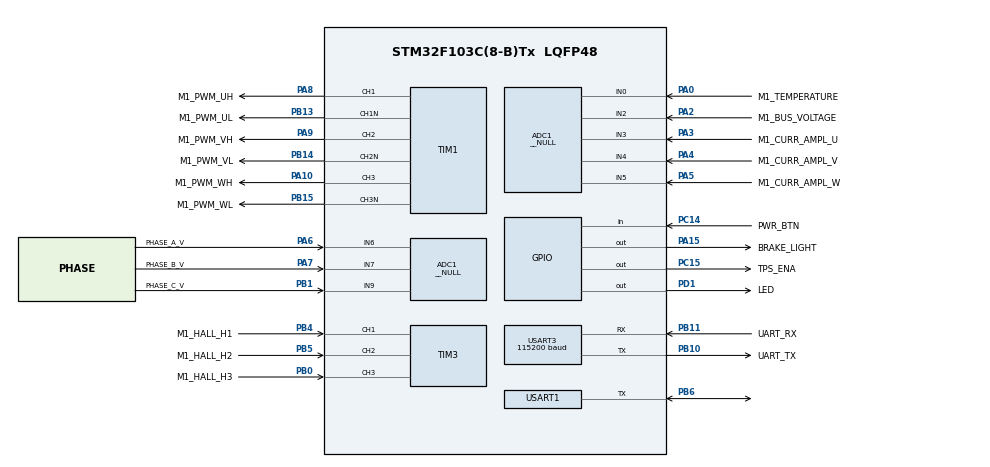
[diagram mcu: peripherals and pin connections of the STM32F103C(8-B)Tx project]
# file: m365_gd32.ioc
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ADC1.Channel-1\#ChannelInjectedConversion=ADC_CHANNEL_3
ADC1.Channel-1\#ChannelRegularConversion=ADC_CHANNEL_2
ADC1.Channel-2\#ChannelInjectedConversion=ADC_CHANNEL_4
ADC1.Channel-2\#ChannelRegularConversion=ADC_CHANNEL_0
ADC1.Channel-3\#ChannelInjectedConversion=ADC_CHANNEL_5
ADC1.Channel-4\#ChannelRegularConversion=ADC_CHANNEL_6
ADC1.Channel-5\#ChannelRegularConversion=ADC_CHANNEL_7
ADC1.Channel-6\#ChannelRegularConversion=ADC_CHANNEL_9
ADC1.ContinuousConvMode=DISABLE
ADC1.DataAlign=ADC_DATAALIGN_LEFT
ADC1.DiscontinuousConvMode=DISABLE
ADC1.EnableAnalogWatchDog=false
ADC1.EnableInjectedConversion=ENABLE
ADC1.EnableRegularConversion=ENABLE
ADC1.ExternalTrigConv=ADC_SOFTWARE_START
ADC1.ExternalTrigInjecConv=ADC_EXTERNALTRIGINJECCONV_T1_CC4
ADC1.InjNumberOfConversion=3
ADC1.InjectedConvMode=Discontinuous
ADC1.InjectedOffset-1\#ChannelInjectedConversion=0
ADC1.InjectedOffset-2\#ChannelInjectedConversion=0
ADC1.InjectedOffset-3\#ChannelInjectedConversion=0
ADC1.Mode=__NULL
ADC1.NbrOfConversion=5
ADC1.NbrOfConversionFlag=1
ADC1.Rank-1\#ChannelRegularConversion=1
ADC1.Rank-2\#ChannelRegularConversion=2
ADC1.Rank-4\#ChannelRegularConversion=3
ADC1.Rank-5\#ChannelRegularConversion=4
ADC1.Rank-6\#ChannelRegularConversion=5
ADC1.SamplingTime-1\#ChannelInjectedConversion=ADC_SAMPLETIME_1CYCLE_5
ADC1.SamplingTime-1\#ChannelRegularConversion=ADC_SAMPLETIME_1CYCLE_5
ADC1.SamplingTime-2\#ChannelInjectedConversion=ADC_SAMPLETIME_1CYCLE_5
ADC1.SamplingTime-2\#ChannelRegularConversion=ADC_SAMPLETIME_1CYCLE_5
ADC1.SamplingTime-3\#ChannelInjectedConversion=ADC_SAMPLETIME_1CYCLE_5
ADC1.SamplingTime-4\#ChannelRegularConversion=ADC_SAMPLETIME_1CYCLE_5
ADC1.SamplingTime-5\#ChannelRegularConversion=ADC_SAMPLETIME_1CYCLE_5
ADC1.SamplingTime-6\#ChannelRegularConversion=ADC_SAMPLETIME_1CYCLE_5
ADC1.ScanConvMode=ADC_SCAN_ENABLE
ADC1.master=1
ADC2.Channel-1\#ChannelInjectedConversion=ADC_CHANNEL_3
ADC2.Channel-2\#ChannelInjectedConversion=ADC_CHANNEL_4
ADC2.Channel-3\#ChannelInjectedConversion=ADC_CHANNEL_5
ADC2.ContinuousConvMode=DISABLE
ADC2.DataAlign=ADC_DATAALIGN_LEFT
ADC2.DiscontinuousConvMode=DISABLE
ADC2.EnableAnalogWatchDog=false
ADC2.EnableInjectedConversion=ENABLE
ADC2.EnableRegularConversion=DISABLE
ADC2.ExternalTrigInjecConv=ADC_EXTERNALTRIGINJECCONV_T1_CC4
ADC2.ExternalTrigInjecConvEdge=ADC_EXTERNALTRIGINJECCONVEDGE_RISING
ADC2.InjNumberOfConversion=3
ADC2.InjectedConvMode=Discontinuous
ADC2.InjectedOffset-1\#ChannelInjectedConversion=0
ADC2.InjectedOffset-2\#ChannelInjectedConversion=0
ADC2.InjectedOffset-3\#ChannelInjectedConversion=0
ADC2.Mode=__NULL
ADC2.Rank-1\#ChannelInjectedConversion=1
ADC2.Rank-2\#ChannelInjectedConversion=2
ADC2.Rank-3\#ChannelInjectedConversion=3
ADC2.SamplingTime-1\#ChannelInjectedConversion=ADC_SAMPLETIME_1CYCLE_5
ADC2.SamplingTime-2\#ChannelInjectedConversion=ADC_SAMPLETIME_1CYCLE_5
ADC2.SamplingTime-3\#ChannelInjectedConversion=ADC_SAMPLETIME_1CYCLE_5
ADC2.ScanConvMode=ADC_SCAN_ENABLE
Dma.ADC1.0.Direction=DMA_PERIPH_TO_MEMORY
Dma.ADC1.0.Instance=DMA1_Channel1
Dma.ADC1.0.MemDataAlignment=DMA_MDATAALIGN_HALFWORD
Dma.ADC1.0.MemInc=DMA_MINC_DISABLE
Dma.ADC1.0.Mode=DMA_CIRCULAR
Dma.ADC1.0.PeriphDataAlignment=DMA_PDATAALIGN_HALFWORD
Dma.ADC1.0.PeriphInc=DMA_PINC_DISABLE
Dma.ADC1.0.Priority=DMA_PRIORITY_LOW
Dma.Request0=ADC1
Dma.Request1=USART1_TX
Dma.Request2=USART1_RX
Dma.Request3=USART3_RX
Dma.Request4=USART3_TX
Dma.USART1_RX.2.Direction=DMA_PERIPH_TO_MEMORY
Dma.USART1_RX.2.Instance=DMA1_Channel5
Dma.USART1_RX.2.MemDataAlignment=DMA_MDATAALIGN_BYTE
Dma.USART1_RX.2.MemInc=DMA_MINC_ENABLE
Dma.USART1_RX.2.Mode=DMA_CIRCULAR
Dma.USART1_RX.2.PeriphDataAlignment=DMA_PDATAALIGN_BYTE
Dma.USART1_RX.2.PeriphInc=DMA_PINC_DISABLE
Dma.USART1_RX.2.Priority=DMA_PRIORITY_LOW
Dma.USART1_TX.1.Direction=DMA_MEMORY_TO_PERIPH
Dma.USART1_TX.1.Instance=DMA1_Channel4
Dma.USART1_TX.1.MemDataAlignment=DMA_MDATAALIGN_BYTE
Dma.USART1_TX.1.MemInc=DMA_MINC_ENABLE
Dma.USART1_TX.1.Mode=DMA_NORMAL
Dma.USART1_TX.1.PeriphDataAlignment=DMA_PDATAALIGN_BYTE
Dma.USART1_TX.1.PeriphInc=DMA_PINC_DISABLE
Dma.USART1_TX.1.Priority=DMA_PRIORITY_LOW
Dma.USART3_RX.3.Direction=DMA_PERIPH_TO_MEMORY
Dma.USART3_RX.3.Instance=DMA1_Channel3
Dma.USART3_RX.3.MemDataAlignment=DMA_MDATAALIGN_BYTE
Dma.USART3_RX.3.MemInc=DMA_MINC_ENABLE
Dma.USART3_RX.3.Mode=DMA_CIRCULAR
Dma.USART3_RX.3.PeriphDataAlignment=DMA_PDATAALIGN_BYTE
Dma.USART3_RX.3.PeriphInc=DMA_PINC_DISABLE
Dma.USART3_RX.3.Priority=DMA_PRIORITY_LOW
Dma.USART3_TX.4.Direction=DMA_MEMORY_TO_PERIPH
Dma.USART3_TX.4.Instance=DMA1_Channel2
Dma.USART3_TX.4.MemDataAlignment=DMA_MDATAALIGN_BYTE
Dma.USART3_TX.4.MemInc=DMA_MINC_ENABLE
Dma.USART3_TX.4.Mode=DMA_NORMAL
Dma.USART3_TX.4.PeriphDataAlignment=DMA_PDATAALIGN_BYTE
Dma.USART3_TX.4.PeriphInc=DMA_PINC_DISABLE
Dma.USART3_TX.4.Priority=DMA_PRIORITY_LOW
Mcu.Family=STM32F1
Mcu.Name=STM32F103C(8-B)Tx
Mcu.Package=LQFP48
NVIC.ADC1_2_IRQn=true\:2\:0\:true\:true\:false\:1\:true\:true
NVIC.DMA1_Channel1_IRQn=true\:0\:0\:true\:true\:false\:4\:true\:true
NVIC.DMA1_Channel2_IRQn=true\:5\:0\:true\:false\:true\:false\:true
NVIC.DMA1_Channel3_IRQn=true\:5\:0\:true\:false\:true\:false\:true
NVIC.DMA1_Channel4_IRQn=true\:5\:0\:true\:false\:true\:false\:true
NVIC.DMA1_Channel5_IRQn=true\:5\:0\:true\:false\:true\:false\:true
NVIC.PriorityGroup=NVIC_PRIORITYGROUP_4
NVIC.TIM1_BRK_IRQn=true\:4\:0\:true\:true\:false\:3\:true\:true
NVIC.TIM1_UP_IRQn=true\:0\:0\:true\:true\:false\:2\:true\:true
NVIC.TIM3_IRQn=true\:3\:0\:true\:true\:false\:5\:true\:true
NVIC.TIM4_IRQn=true\:15\:0\:false\:false\:true\:false\:true
NVIC.TimeBase=TIM4_IRQn
NVIC.TimeBaseIP=TIM4
PA0-WKUP.GPIO_Label=M1_TEMPERATURE
PA0-WKUP.Signal=ADCx_IN0
PA10.GPIO_Label=M1_PWM_WH
PA10.GPIO_PuPd=GPIO_PULLDOWN
PA10.GPIO_Speed=GPIO_SPEED_FREQ_HIGH
PA10.Signal=S_TIM1_CH3
PA13.Mode=Serial_Wire
PA13.Signal=SYS_JTMS-SWDIO
PA14.Mode=Serial_Wire
PA14.Signal=SYS_JTCK-SWCLK
PA15.GPIO_Label=BRAKE_LIGHT
PA15.GPIO_ModeDefaultOutputPP=GPIO_MODE_OUTPUT_OD
PA15.Signal=GPIO_Output
PA2.GPIO_Label=M1_BUS_VOLTAGE
PA2.Signal=ADCx_IN2
PA3.GPIO_Label=M1_CURR_AMPL_U
PA3.Signal=SharedAnalog_PA3
PA4.GPIO_Label=M1_CURR_AMPL_V
PA4.Signal=SharedAnalog_PA4
PA5.GPIO_Label=M1_CURR_AMPL_W
PA5.Signal=SharedAnalog_PA5
PA6.GPIO_Label=PHASE_A_V
PA6.Signal=ADCx_IN6
PA7.GPIO_Label=PHASE_B_V
PA7.Signal=ADCx_IN7
PA8.GPIO_Label=M1_PWM_UH
PA8.GPIO_PuPd=GPIO_PULLDOWN
PA8.GPIO_Speed=GPIO_SPEED_FREQ_HIGH
PA8.Signal=S_TIM1_CH1
PA9.GPIO_Label=M1_PWM_VH
PA9.GPIO_PuPd=GPIO_PULLDOWN
PA9.GPIO_Speed=GPIO_SPEED_FREQ_HIGH
PA9.Signal=S_TIM1_CH2
PB0.GPIO_Label=M1_HALL_H3
PB0.GPIO_Speed=GPIO_SPEED_FREQ_HIGH
PB0.Signal=S_TIM3_CH3
PB1.GPIO_Label=PHASE_C_V
PB1.Signal=ADCx_IN9
PB10.GPIO_Label=UART_TX
PB10.GPIO_Mode=GPIO_MODE_AF_PP
PB10.GPIO_PuPd=GPIO_NOPULL
PB10.GPIO_Speed=GPIO_SPEED_FREQ_LOW
PB10.Mode=Asynchronous
PB10.Signal=USART3_TX
PB11.GPIO_Label=UART_RX
PB11.GPIO_Mode=GPIO_MODE_INPUT
PB11.GPIO_PuPd=GPIO_NOPULL
PB11.GPIO_Speed=GPIO_SPEED_FREQ_LOW
PB11.Mode=Asynchronous
PB11.Signal=USART3_RX
PB13.GPIO_Label=M1_PWM_UL
PB13.GPIO_PuPd=GPIO_PULLDOWN
PB13.GPIO_Speed=GPIO_SPEED_FREQ_HIGH
PB13.Mode=PWM Generation1 CH1 CH1N
PB13.Signal=TIM1_CH1N
PB14.GPIO_Label=M1_PWM_VL
PB14.GPIO_PuPd=GPIO_PULLDOWN
PB14.GPIO_Speed=GPIO_SPEED_FREQ_HIGH
PB14.Mode=PWM Generation2 CH2 CH2N
PB14.Signal=TIM1_CH2N
PB15.GPIO_Label=M1_PWM_WL
PB15.GPIO_PuPd=GPIO_PULLDOWN
PB15.GPIO_Speed=GPIO_SPEED_FREQ_HIGH
PB15.Mode=PWM Generation3 CH3 CH3N
PB15.Signal=TIM1_CH3N
PB4.GPIO_Label=M1_HALL_H1
PB4.GPIO_Speed=GPIO_SPEED_FREQ_HIGH
PB4.Signal=S_TIM3_CH1
PB5.GPIO_Label=M1_HALL_H2
PB5.GPIO_Speed=GPIO_SPEED_FREQ_HIGH
PB5.Signal=S_TIM3_CH2
PB6.Mode=Half_duplex(single_wire_mode)
PB6.Signal=USART1_TX
PC14-OSC32_IN.GPIO_Label=PWR_BTN
PC14-OSC32_IN.Signal=GPIO_Input
PC15-OSC32_OUT.GPIO_Label=TPS_ENA
PC15-OSC32_OUT.PinState=GPIO_PIN_SET
PC15-OSC32_OUT.Signal=GPIO_Output
PD1-OSC_OUT.GPIO_Label=LED
PD1-OSC_OUT.Signal=GPIO_Output
ProjectManager.HeapSize=0x200
ProjectManager.StackSize=0x400
ProjectManager.TargetToolchain=STM32CubeIDE
RCC.ADCPresc=RCC_ADCPCLK2_DIV6
RCC.AHBFreq_Value=64000000
RCC.APB1CLKDivider=RCC_HCLK_DIV2
RCC.APB1Freq_Value=32000000
RCC.APB1TimFreq_Value=64000000
RCC.APB2Freq_Value=64000000
RCC.APB2TimFreq_Value=64000000
RCC.EnbaleCSS=true
RCC.HCLKFreq_Value=64000000
RCC.PLLMUL=RCC_PLL_MUL16
RCC.RTCClockSelection=RCC_RTCCLKSOURCE_LSI
RCC.SYSCLKFreq_VALUE=64000000
RCC.SYSCLKSource=RCC_SYSCLKSOURCE_PLLCLK
RCC.USBFreq_Value=64000000
SH.ADCx_IN0.0=ADC1_IN0,IN0
SH.ADCx_IN2.0=ADC1_IN2,IN2
SH.ADCx_IN6.0=ADC1_IN6,IN6
SH.ADCx_IN7.0=ADC1_IN7,IN7
SH.ADCx_IN9.0=ADC1_IN9,IN9
SH.S_TIM1_CH1.0=TIM1_CH1,PWM Generation1 CH1 CH1N
SH.S_TIM1_CH2.0=TIM1_CH2,PWM Generation2 CH2 CH2N
SH.S_TIM1_CH3.0=TIM1_CH3,PWM Generation3 CH3 CH3N
SH.S_TIM3_CH1.0=TIM3_CH1,Xored_Inputs_Hall_Sensor_Interface
SH.S_TIM3_CH2.0=TIM3_CH2,Xored_Inputs_Hall_Sensor_Interface
SH.S_TIM3_CH3.0=TIM3_CH3,Xored_Inputs_Hall_Sensor_Interface
SH.SharedAnalog_PA3.0=ADC1_IN3,IN3
SH.SharedAnalog_PA3.1=ADC2_IN3,IN3
SH.SharedAnalog_PA4.0=ADC1_IN4,IN4
SH.SharedAnalog_PA4.1=ADC2_IN4,IN4
SH.SharedAnalog_PA5.0=ADC1_IN5,IN5
SH.SharedAnalog_PA5.1=ADC2_IN5,IN5
TIM1.AutomaticOutput=TIM_AUTOMATICOUTPUT_DISABLE
TIM1.BreakPolarity=TIM_BREAKPOLARITY_LOW
TIM1.BreakState=TIM_BREAK_DISABLE
TIM1.Channel-PWM\ Generation1\ CH1\ CH1N=TIM_CHANNEL_1
TIM1.Channel-PWM\ Generation2\ CH2\ CH2N=TIM_CHANNEL_2
TIM1.Channel-PWM\ Generation3\ CH3\ CH3N=TIM_CHANNEL_3
TIM1.Channel-PWM\ Generation4\ No\ Output=TIM_CHANNEL_4
TIM1.ClockDivision=TIM_CLOCKDIVISION_DIV2
TIM1.CounterMode=TIM_COUNTERMODE_CENTERALIGNED1
TIM1.DeadTime=((DEAD_TIME_COUNTS) / 2)
TIM1.LockLevel=TIM_LOCKLEVEL_1
TIM1.OCIdleState_1=TIM_OCIDLESTATE_RESET
TIM1.OCIdleState_2=TIM_OCIDLESTATE_RESET
TIM1.OCIdleState_3=TIM_OCIDLESTATE_RESET
TIM1.OCMode_PWM-PWM\ Generation4\ No\ Output=TIM_OCMODE_PWM2
TIM1.OCNIdleState_1=TIM_OCNIDLESTATE_RESET
TIM1.OCNIdleState_2=TIM_OCNIDLESTATE_RESET
TIM1.OCNIdleState_3=TIM_OCNIDLESTATE_RESET
TIM1.OCNPolarity_1=TIM_OCNPOLARITY_HIGH
TIM1.OCNPolarity_2=TIM_OCNPOLARITY_HIGH
TIM1.OCNPolarity_3=TIM_OCNPOLARITY_HIGH
TIM1.OCPolarity_1=TIM_OCPOLARITY_HIGH
TIM1.OCPolarity_2=TIM_OCPOLARITY_HIGH
TIM1.OCPolarity_3=TIM_OCPOLARITY_HIGH
TIM1.OffStateIDLEMode=TIM_OSSI_ENABLE
TIM1.OffStateRunMode=TIM_OSSR_ENABLE
TIM1.Period=((PWM_PERIOD_CYCLES) / 2)
TIM1.Prescaler=((TIM_CLOCK_DIVIDER) - 1)
TIM1.Pulse-PWM\ Generation1\ CH1=((PWM_PERIOD_CYCLES) / 4)
TIM1.Pulse-PWM\ Generation2\ CH2=((PWM_PERIOD_CYCLES) / 4)
TIM1.Pulse-PWM\ Generation3\ CH3=((PWM_PERIOD_CYCLES) / 4)
TIM1.Pulse-PWM\ Generation4\ No\ Output=(((PWM_PERIOD_CYCLES) / 2) - (HTMIN))
TIM1.RepetitionCounter=(REP_COUNTER)
TIM1.TIM_MasterOutputTrigger=TIM_TRGO_RESET
TIM1.TIM_MasterSlaveMode=TIM_MASTERSLAVEMODE_DISABLE
TIM3.IC1Filter=M1_HALL_IC_FILTER
TIM3.Period=M1_HALL_TIM_PERIOD
USART1.VirtualMode=VM_ASYNC
USART3.BaudRate=115200
USART3.VirtualMode=VM_ASYNC
USART3.VirtualMode-Asynchronous=VM_ASYNC
USART3.WordLength=WORDLENGTH_8B
VP_SYS_VS_tim4.Mode=TIM4
VP_TIM1_VS_ClockSourceITR.Mode=TriggerSource_ITR1
VP_TIM1_VS_ControllerModeTrigger.Mode=Trigger Mode
VP_TIM1_VS_no_output4.Mode=PWM Generation4 No Output
VP_TIM3_VS_ClockSourceINT.Mode=Internal
board=custom

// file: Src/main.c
/* USER CODE BEGIN Header */
/**
  ******************************************************************************
  * @file           : main.c
  * @brief          : Main program body
  ******************************************************************************
  * @attention
  *
  * <h2><center>&copy; Copyright (c) 2021 STMicroelectronics.
  * All rights reserved.</center></h2>
  *
  * This software component is licensed by ST under Ultimate Liberty license
  * SLA0044, the "License"; You may not use this file except in compliance with
  * the License. You may obtain a copy of the License at:
  *                             www.st.com/SLA0044
  *
  ******************************************************************************
  */
/* USER CODE END Header */
#include "main.h"

/* USER CODE BEGIN Includes */
#include "cmsis_os.h"
#include "FreeRTOS.h"
#include "task.h"
#include "task_init.h"
#include "motorcontrol.h"
#include "conf_general.h"
#include "app.h"
#include "product.h"
#ifdef M365_gd32
#include "gd32.h"
#endif

/* USER CODE END Includes */

ADC_HandleTypeDef hadc1;
ADC_HandleTypeDef hadc2;
DMA_HandleTypeDef hdma_adc1;

TIM_HandleTypeDef htim1;
TIM_HandleTypeDef htim3;

UART_HandleTypeDef huart1;
UART_HandleTypeDef huart3;
DMA_HandleTypeDef hdma_usart1_tx;
DMA_HandleTypeDef hdma_usart1_rx;
DMA_HandleTypeDef hdma_usart3_rx;
DMA_HandleTypeDef hdma_usart3_tx;

/* USER CODE BEGIN PV */
/* Definitions for mediumFrequency */

/* USER CODE END PV */

void SystemClock_Config(void);
static void MX_GPIO_Init(void);
static void MX_DMA_Init(void);
static void MX_ADC1_Init(void);
static void MX_ADC2_Init(void);
static void MX_TIM1_Init(void);
static void MX_TIM3_Init(void);
static void MX_USART3_UART_Init(void);
static void MX_USART1_UART_Init(void);
static void MX_NVIC_Init(void);
/* USER CODE BEGIN PFP */
void startMediumFrequencyTask(void *argument);
extern void StartSafetyTask(void *argument);

/* USER CODE END PFP */

int main(void)
{
  /* USER CODE BEGIN 1 */
#ifdef M365_gd32
	SCB->CPACR |= (0x3 << 10 * 2 | 0x3 << 11 * 2);  //Enable FPU
#endif
  /* USER CODE END 1 */

  /* MCU Configuration--------------------------------------------------------*/

  /* Reset of all peripherals, Initializes the Flash interface and the Systick. */
  HAL_Init();

  /* USER CODE BEGIN Init */
#ifndef M365_gd32
  /* USER CODE END Init */

  /* Configure the system clock */
  SystemClock_Config();

  /* USER CODE BEGIN SysInit */
#else

  SystemClock_Config_gd32();
#endif
  /* USER CODE END SysInit */

  /* Initialize all configured peripherals */
  MX_GPIO_Init();
  MX_DMA_Init();
  MX_ADC1_Init();
  MX_ADC2_Init();
  MX_TIM1_Init();
  MX_TIM3_Init();
  MX_USART3_UART_Init();
  MX_USART1_UART_Init();

  /* Initialize interrupts */
  MX_NVIC_Init();
  /* USER CODE BEGIN 2 */

  HAL_ADCEx_Calibration_Start(&hadc1);
  HAL_ADCEx_Calibration_Start(&hadc2);

  MX_MotorControl_Init();
  HAL_Delay(100);

  conf_general_init();

  //osKernelInitialize();

  /* USER CODE BEGIN RTOS_MUTEX */
  /* add mutexes, ... */
  HAL_GPIO_WritePin(TPS_ENA_GPIO_Port, TPS_ENA_Pin, GPIO_PIN_SET);
  /* USER CODE END RTOS_MUTEX */

  /* USER CODE BEGIN RTOS_SEMAPHORES */
  /* add semaphores, ... */
  /* USER CODE END RTOS_SEMAPHORES */

  /* USER CODE BEGIN RTOS_TIMERS */
  /* start timers, add new ones, ... */
  /* USER CODE END RTOS_TIMERS */

  /* USER CODE BEGIN RTOS_QUEUES */
  /* add queues, ... */
  /* USER CODE END RTOS_QUEUES */

  /* Create the thread(s) */
  /* USER CODE BEGIN RTOS_THREADS */
  /* add threads, ... */
  TaskHandle_t mediumFrequencyHandle;

  TaskHandle_t safetyHandle;

  xTaskCreate(startMediumFrequencyTask, "medTSK", 128, NULL, PRIO_NORMAL, &mediumFrequencyHandle);
  xTaskCreate(StartSafetyTask, "safety", 128, NULL, PRIO_HIGHER, &safetyHandle);

  task_init(); //bring up user tasks
  HAL_GPIO_WritePin(TPS_ENA_GPIO_Port, TPS_ENA_Pin, GPIO_PIN_SET);

  /* USER CODE END RTOS_THREADS */

  /* USER CODE BEGIN RTOS_EVENTS */
  /* add events, ... */
  /* USER CODE END RTOS_EVENTS */

  /* Start scheduler */
  vTaskStartScheduler();

  /* We should never ge*/

  /* USER CODE END 2 */

  /* Infinite loop */
  /* USER CODE BEGIN WHILE */
  vTaskSwitchContext();
  while (1)
  {
    /* USER CODE END WHILE */

  }
}

#define REG32(addr)                  	(*(volatile uint32_t *)(uint32_t)(addr))
#define AHB1_BUS_BASE         			((uint32_t)0x40018000U)        /*!< ahb1 base address                */
#define RCU_BASE              			(AHB1_BUS_BASE + 0x00009000U)  /*!< RCU base address                 */
#define RCU                             RCU_BASE

#define RCU_CTL                         REG32(RCU + 0x00U)        /*!< control register */
#define RCU_CFG0                        REG32(RCU + 0x04U)        /*!< clock configuration register 0 */
#define RCU_INT                         REG32(RCU + 0x08U)        /*!< clock interrupt register */
#define RCU_APB2RST                     REG32(RCU + 0x0CU)        /*!< APB2 reset register */
#define RCU_APB1RST                     REG32(RCU + 0x10U)        /*!< APB1 reset register */
#define RCU_AHBEN                       REG32(RCU + 0x14U)        /*!< AHB enable register */
#define RCU_APB2EN                      REG32(RCU + 0x18U)        /*!< APB2 enable register */
#define RCU_APB1EN                      REG32(RCU + 0x1CU)        /*!< APB1 enable register */
#define RCU_BDCTL                       REG32(RCU + 0x20U)        /*!< backup domain control register */
#define RCU_RSTSCK                      REG32(RCU + 0x24U)        /*!< reset source / clock register */
#define RCU_CFG1                        REG32(RCU + 0x2CU)        /*!< clock configuration register 1 */
#define RCU_DSV                         REG32(RCU + 0x34U)        /*!< deep-sleep mode voltage register */
#define RCU_ADDCTL                      REG32(RCU + 0xC0U)        /*!< Additional clock control register */
#define RCU_ADDINT                      REG32(RCU + 0xCCU)        /*!< Additional clock interrupt register */
#define RCU_ADDAPB1RST                  REG32(RCU + 0xE0U)        /*!< APB1 additional reset register */
#define RCU_ADDAPB1EN                   REG32(RCU + 0xE4U)        /*!< APB1 additional enable register */

void SystemClock_Config(void)
{
  RCC_OscInitTypeDef RCC_OscInitStruct = {0};
  RCC_ClkInitTypeDef RCC_ClkInitStruct = {0};
  RCC_PeriphCLKInitTypeDef PeriphClkInit = {0};

  /** Initializes the RCC Oscillators according to the specified parameters
  * in the RCC_OscInitTypeDef structure.
  */

  RCU_CFG1 |= ((1<<30) | (1<<0)); // PLLPRESEL 1 (48Mhz RC); PREDV0 (/2) = 24 Mhz
  RCU_CFG0 |= (1<<17);

  RCU_ADDCTL |= ((1<<16) | (1<<0));
  while((RCU_ADDCTL & (1<<17))){

  }

  RCC_OscInitStruct.OscillatorType = RCC_OSCILLATORTYPE_HSE;
  RCC_OscInitStruct.HSIState = RCC_HSI_ON;
  RCC_OscInitStruct.HSICalibrationValue = RCC_HSICALIBRATION_DEFAULT;
  RCC_OscInitStruct.PLL.PLLState = RCC_PLL_ON;
  RCC_OscInitStruct.PLL.PLLSource = RCC_PLLSOURCE_HSE;
  RCC_OscInitStruct.PLL.PLLMUL = RCC_PLL_MUL5;
  RCC_OscInitStruct.HSEPredivValue = RCC_HSE_PREDIV_DIV2;
  if (HAL_RCC_OscConfig(&RCC_OscInitStruct) != HAL_OK)
  {
    Error_Handler();
  }
  /** Initializes the CPU, AHB and APB buses clocks
  */
  RCC_ClkInitStruct.ClockType = RCC_CLOCKTYPE_HCLK|RCC_CLOCKTYPE_SYSCLK
                              |RCC_CLOCKTYPE_PCLK1|RCC_CLOCKTYPE_PCLK2;
  RCC_ClkInitStruct.SYSCLKSource = RCC_SYSCLKSOURCE_PLLCLK;
  RCC_ClkInitStruct.AHBCLKDivider = RCC_SYSCLK_DIV1;
  RCC_ClkInitStruct.APB1CLKDivider = RCC_HCLK_DIV4;
  RCC_ClkInitStruct.APB2CLKDivider = RCC_HCLK_DIV4;

  if (HAL_RCC_ClockConfig(&RCC_ClkInitStruct, FLASH_LATENCY_2) != HAL_OK)
  {
    Error_Handler();
  }
  PeriphClkInit.PeriphClockSelection = RCC_PERIPHCLK_ADC;
  PeriphClkInit.AdcClockSelection = RCC_ADCPCLK2_DIV4;
  if (HAL_RCCEx_PeriphCLKConfig(&PeriphClkInit) != HAL_OK)
  {
    Error_Handler();
  }
  /** Enables the Clock Security System
  */
  HAL_RCC_EnableCSS();
}

/**
  * @brief NVIC Configuration.
  * @retval None
  */
static void MX_NVIC_Init(void)
{
  /* ADC1_2_IRQn interrupt configuration */
  HAL_NVIC_SetPriority(ADC1_2_IRQn, 2, 0);
  HAL_NVIC_EnableIRQ(ADC1_2_IRQn);
  /* TIM1_UP_IRQn interrupt configuration */
  HAL_NVIC_SetPriority(TIM1_UP_IRQn, 0, 0);
  HAL_NVIC_EnableIRQ(TIM1_UP_IRQn);
  /* TIM1_BRK_IRQn interrupt configuration */
  HAL_NVIC_SetPriority(TIM1_BRK_IRQn, 4, 0);
  HAL_NVIC_EnableIRQ(TIM1_BRK_IRQn);
  /* DMA1_Channel1_IRQn interrupt configuration */
  HAL_NVIC_SetPriority(DMA1_Channel1_IRQn, 0, 0);
  HAL_NVIC_EnableIRQ(DMA1_Channel1_IRQn);
  /* TIM3_IRQn interrupt configuration */
  HAL_NVIC_SetPriority(TIM3_IRQn, 3, 0);
  HAL_NVIC_EnableIRQ(TIM3_IRQn);
}

static void MX_ADC1_Init(void)
{

  ADC_InjectionConfTypeDef sConfigInjected = {0};
  ADC_ChannelConfTypeDef sConfig = {0};

  /** Common config
  */
  hadc1.Instance = ADC1;
  hadc1.Init.ScanConvMode = ADC_SCAN_ENABLE;
  hadc1.Init.ContinuousConvMode = DISABLE;
  hadc1.Init.DiscontinuousConvMode = DISABLE;
  hadc1.Init.ExternalTrigConv = ADC_SOFTWARE_START;
  hadc1.Init.DataAlign = ADC_DATAALIGN_LEFT;
  hadc1.Init.NbrOfConversion = 5;
  if (HAL_ADC_Init(&hadc1) != HAL_OK)
  {
    Error_Handler();
  }
  /** Configure Injected Channel
  */
  sConfigInjected.InjectedChannel = ADC_CHANNEL_3;
  sConfigInjected.InjectedRank = ADC_INJECTED_RANK_1;
  sConfigInjected.InjectedNbrOfConversion = 3;
  sConfigInjected.InjectedSamplingTime = ADC_SAMPLETIME_1CYCLE_5;
  sConfigInjected.ExternalTrigInjecConv = ADC_EXTERNALTRIGINJECCONV_T1_CC4;
  sConfigInjected.AutoInjectedConv = DISABLE;
  sConfigInjected.InjectedDiscontinuousConvMode = ENABLE;
  sConfigInjected.InjectedOffset = 0;
  if (HAL_ADCEx_InjectedConfigChannel(&hadc1, &sConfigInjected) != HAL_OK)
  {
    Error_Handler();
  }
  /** Configure Injected Channel
  */
  sConfigInjected.InjectedChannel = ADC_CHANNEL_4;
  if (HAL_ADCEx_InjectedConfigChannel(&hadc1, &sConfigInjected) != HAL_OK)
  {
    Error_Handler();
  }
  /** Configure Injected Channel
  */
  sConfigInjected.InjectedChannel = ADC_CHANNEL_5;
  if (HAL_ADCEx_InjectedConfigChannel(&hadc1, &sConfigInjected) != HAL_OK)
  {
    Error_Handler();
  }
  /** Configure Regular Channel
  */
  sConfig.Channel = ADC_CHANNEL_2;
  sConfig.Rank = ADC_REGULAR_RANK_1;
  sConfig.SamplingTime = ADC_SAMPLETIME_1CYCLE_5;
  if (HAL_ADC_ConfigChannel(&hadc1, &sConfig) != HAL_OK)
  {
    Error_Handler();
  }
  /** Configure Regular Channel
  */
  sConfig.Channel = ADC_CHANNEL_0;
  sConfig.Rank = ADC_REGULAR_RANK_2;
  if (HAL_ADC_ConfigChannel(&hadc1, &sConfig) != HAL_OK)
  {
    Error_Handler();
  }
  /** Configure Regular Channel
  */
  sConfig.Channel = ADC_CHANNEL_6;
  sConfig.Rank = ADC_REGULAR_RANK_3;
  if (HAL_ADC_ConfigChannel(&hadc1, &sConfig) != HAL_OK)
  {
    Error_Handler();
  }
  /** Configure Regular Channel
  */
  sConfig.Channel = ADC_CHANNEL_7;
  sConfig.Rank = ADC_REGULAR_RANK_4;
  if (HAL_ADC_ConfigChannel(&hadc1, &sConfig) != HAL_OK)
  {
    Error_Handler();
  }
  /** Configure Regular Channel
  */
  sConfig.Channel = ADC_CHANNEL_9;
  sConfig.Rank = ADC_REGULAR_RANK_5;
  if (HAL_ADC_ConfigChannel(&hadc1, &sConfig) != HAL_OK)
  {
    Error_Handler();
  }

}

static void MX_ADC2_Init(void)
{

  ADC_InjectionConfTypeDef sConfigInjected = {0};

  /** Common config
  */
  hadc2.Instance = ADC2;
  hadc2.Init.ScanConvMode = ADC_SCAN_ENABLE;
  hadc2.Init.ContinuousConvMode = DISABLE;
  hadc2.Init.DiscontinuousConvMode = DISABLE;
  hadc2.Init.ExternalTrigConv = ADC_SOFTWARE_START;
  hadc2.Init.DataAlign = ADC_DATAALIGN_LEFT;
  hadc2.Init.NbrOfConversion = 1;
  if (HAL_ADC_Init(&hadc2) != HAL_OK)
  {
    Error_Handler();
  }
  /** Configure Injected Channel
  */
  sConfigInjected.InjectedChannel = ADC_CHANNEL_3;
  sConfigInjected.InjectedRank = 1;
  sConfigInjected.InjectedNbrOfConversion = 3;
  sConfigInjected.InjectedSamplingTime = ADC_SAMPLETIME_1CYCLE_5;
  sConfigInjected.ExternalTrigInjecConv = ADC_EXTERNALTRIGINJECCONV_T1_CC4;
  sConfigInjected.AutoInjectedConv = DISABLE;
  sConfigInjected.InjectedDiscontinuousConvMode = ENABLE;
  sConfigInjected.InjectedOffset = 0;
  if (HAL_ADCEx_InjectedConfigChannel(&hadc2, &sConfigInjected) != HAL_OK)
  {
    Error_Handler();
  }
  /** Configure Injected Channel
  */
  sConfigInjected.InjectedChannel = ADC_CHANNEL_4;
  sConfigInjected.InjectedRank = 2;
  if (HAL_ADCEx_InjectedConfigChannel(&hadc2, &sConfigInjected) != HAL_OK)
  {
    Error_Handler();
  }
  /** Configure Injected Channel
  */
  sConfigInjected.InjectedChannel = ADC_CHANNEL_5;
  sConfigInjected.InjectedRank = 3;
  if (HAL_ADCEx_InjectedConfigChannel(&hadc2, &sConfigInjected) != HAL_OK)
  {
    Error_Handler();
  }

}

static void MX_TIM1_Init(void)
{

  TIM_SlaveConfigTypeDef sSlaveConfig = {0};
  TIM_MasterConfigTypeDef sMasterConfig = {0};
  TIM_OC_InitTypeDef sConfigOC = {0};
  TIM_BreakDeadTimeConfigTypeDef sBreakDeadTimeConfig = {0};

  htim1.Instance = TIM1;
  htim1.Init.Prescaler = ((TIM_CLOCK_DIVIDER) - 1);
  htim1.Init.CounterMode = TIM_COUNTERMODE_CENTERALIGNED1;
  htim1.Init.Period = ((PWM_PERIOD_CYCLES) / 2);
  htim1.Init.ClockDivision = TIM_CLOCKDIVISION_DIV2;
  htim1.Init.RepetitionCounter = (REP_COUNTER);
  htim1.Init.AutoReloadPreload = TIM_AUTORELOAD_PRELOAD_DISABLE;
  if (HAL_TIM_Base_Init(&htim1) != HAL_OK)
  {
    Error_Handler();
  }
  if (HAL_TIM_PWM_Init(&htim1) != HAL_OK)
  {
    Error_Handler();
  }
  sSlaveConfig.SlaveMode = TIM_SLAVEMODE_TRIGGER;
  sSlaveConfig.InputTrigger = TIM_TS_ITR1;
  if (HAL_TIM_SlaveConfigSynchro(&htim1, &sSlaveConfig) != HAL_OK)
  {
    Error_Handler();
  }
  sMasterConfig.MasterOutputTrigger = TIM_TRGO_RESET;
  sMasterConfig.MasterSlaveMode = TIM_MASTERSLAVEMODE_DISABLE;
  if (HAL_TIMEx_MasterConfigSynchronization(&htim1, &sMasterConfig) != HAL_OK)
  {
    Error_Handler();
  }
  sConfigOC.OCMode = TIM_OCMODE_PWM1;
  sConfigOC.Pulse = 0;
  sConfigOC.OCPolarity = TIM_OCPOLARITY_HIGH;
  sConfigOC.OCNPolarity = TIM_OCNPOLARITY_HIGH;
  sConfigOC.OCFastMode = TIM_OCFAST_DISABLE;
  sConfigOC.OCIdleState = TIM_OCIDLESTATE_RESET;
  sConfigOC.OCNIdleState = TIM_OCNIDLESTATE_RESET;
  if (HAL_TIM_PWM_ConfigChannel(&htim1, &sConfigOC, TIM_CHANNEL_1) != HAL_OK)
  {
    Error_Handler();
  }
  if (HAL_TIM_PWM_ConfigChannel(&htim1, &sConfigOC, TIM_CHANNEL_2) != HAL_OK)
  {
    Error_Handler();
  }
  if (HAL_TIM_PWM_ConfigChannel(&htim1, &sConfigOC, TIM_CHANNEL_3) != HAL_OK)
  {
    Error_Handler();
  }
  sConfigOC.OCMode = TIM_OCMODE_PWM2;
  sConfigOC.Pulse = (((PWM_PERIOD_CYCLES) / 2) - (HTMIN));
  if (HAL_TIM_PWM_ConfigChannel(&htim1, &sConfigOC, TIM_CHANNEL_4) != HAL_OK)
  {
    Error_Handler();
  }
  sBreakDeadTimeConfig.OffStateRunMode = TIM_OSSR_ENABLE;
  sBreakDeadTimeConfig.OffStateIDLEMode = TIM_OSSI_ENABLE;
  sBreakDeadTimeConfig.LockLevel = TIM_LOCKLEVEL_1;
  sBreakDeadTimeConfig.DeadTime = ((DEAD_TIME_COUNTS) / 2);
  sBreakDeadTimeConfig.BreakState = TIM_BREAK_DISABLE;
  sBreakDeadTimeConfig.BreakPolarity = TIM_BREAKPOLARITY_LOW;
  sBreakDeadTimeConfig.AutomaticOutput = TIM_AUTOMATICOUTPUT_DISABLE;
  if (HAL_TIMEx_ConfigBreakDeadTime(&htim1, &sBreakDeadTimeConfig) != HAL_OK)
  {
    Error_Handler();
  }
  HAL_TIM_MspPostInit(&htim1);

}

static void MX_TIM3_Init(void)
{

  TIM_ClockConfigTypeDef sClockSourceConfig = {0};
  TIM_HallSensor_InitTypeDef sConfig = {0};
  TIM_MasterConfigTypeDef sMasterConfig = {0};

  htim3.Instance = TIM3;
  htim3.Init.Prescaler = 0;
  htim3.Init.CounterMode = TIM_COUNTERMODE_UP;
  htim3.Init.Period = M1_HALL_TIM_PERIOD;
  htim3.Init.ClockDivision = TIM_CLOCKDIVISION_DIV1;
  htim3.Init.AutoReloadPreload = TIM_AUTORELOAD_PRELOAD_DISABLE;
  if (HAL_TIM_Base_Init(&htim3) != HAL_OK)
  {
    Error_Handler();
  }
  sClockSourceConfig.ClockSource = TIM_CLOCKSOURCE_INTERNAL;
  if (HAL_TIM_ConfigClockSource(&htim3, &sClockSourceConfig) != HAL_OK)
  {
    Error_Handler();
  }
  sConfig.IC1Polarity = TIM_ICPOLARITY_RISING;
  sConfig.IC1Prescaler = TIM_ICPSC_DIV1;
  sConfig.IC1Filter = M1_HALL_IC_FILTER;
  sConfig.Commutation_Delay = 0;
  if (HAL_TIMEx_HallSensor_Init(&htim3, &sConfig) != HAL_OK)
  {
    Error_Handler();
  }
  sMasterConfig.MasterOutputTrigger = TIM_TRGO_OC2REF;
  sMasterConfig.MasterSlaveMode = TIM_MASTERSLAVEMODE_DISABLE;
  if (HAL_TIMEx_MasterConfigSynchronization(&htim3, &sMasterConfig) != HAL_OK)
  {
    Error_Handler();
  }

}

static void MX_USART1_UART_Init(void)
{

  huart1.Instance = USART1;
  huart1.Init.BaudRate = 115200;
  huart1.Init.WordLength = UART_WORDLENGTH_8B;
  huart1.Init.StopBits = UART_STOPBITS_1;
  huart1.Init.Parity = UART_PARITY_NONE;
  huart1.Init.Mode = UART_MODE_TX_RX;
  huart1.Init.HwFlowCtl = UART_HWCONTROL_NONE;
  huart1.Init.OverSampling = UART_OVERSAMPLING_16;
  if (HAL_HalfDuplex_Init(&huart1) != HAL_OK)
  {
    Error_Handler();
  }

}

static void MX_USART3_UART_Init(void)
{

  huart3.Instance = USART3;
  huart3.Init.BaudRate = 115200;
  huart3.Init.WordLength = UART_WORDLENGTH_8B;
  huart3.Init.StopBits = UART_STOPBITS_1;
  huart3.Init.Parity = UART_PARITY_NONE;
  huart3.Init.Mode = UART_MODE_TX_RX;
  huart3.Init.HwFlowCtl = UART_HWCONTROL_NONE;
  huart3.Init.OverSampling = UART_OVERSAMPLING_16;
  if (HAL_UART_Init(&huart3) != HAL_OK)
  {
    Error_Handler();
  }

}

static void MX_DMA_Init(void)
{

  /* DMA controller clock enable */
  __HAL_RCC_DMA1_CLK_ENABLE();

  /* DMA interrupt init */
  /* DMA1_Channel2_IRQn interrupt configuration */
  HAL_NVIC_SetPriority(DMA1_Channel2_IRQn, 5, 0);
  HAL_NVIC_EnableIRQ(DMA1_Channel2_IRQn);
  /* DMA1_Channel3_IRQn interrupt configuration */
  HAL_NVIC_SetPriority(DMA1_Channel3_IRQn, 5, 0);
  HAL_NVIC_EnableIRQ(DMA1_Channel3_IRQn);
  /* DMA1_Channel4_IRQn interrupt configuration */
  HAL_NVIC_SetPriority(DMA1_Channel4_IRQn, 5, 0);
  HAL_NVIC_EnableIRQ(DMA1_Channel4_IRQn);
  /* DMA1_Channel5_IRQn interrupt configuration */
  HAL_NVIC_SetPriority(DMA1_Channel5_IRQn, 5, 0);
  HAL_NVIC_EnableIRQ(DMA1_Channel5_IRQn);

}

static void MX_GPIO_Init(void)
{
  GPIO_InitTypeDef GPIO_InitStruct = {0};

  /* GPIO Ports Clock Enable */
  __HAL_RCC_GPIOC_CLK_ENABLE();
  __HAL_RCC_GPIOD_CLK_ENABLE();
  __HAL_RCC_GPIOA_CLK_ENABLE();
  __HAL_RCC_GPIOB_CLK_ENABLE();

  /*Configure GPIO pin Output Level */
  HAL_GPIO_WritePin(TPS_ENA_GPIO_Port, TPS_ENA_Pin, GPIO_PIN_SET);

  /*Configure GPIO pin Output Level */
  HAL_GPIO_WritePin(LED_GPIO_Port, LED_Pin, GPIO_PIN_RESET);

  /*Configure GPIO pin Output Level */
  HAL_GPIO_WritePin(BRAKE_LIGHT_GPIO_Port, BRAKE_LIGHT_Pin, GPIO_PIN_RESET);

  /*Configure GPIO pin : PWR_BTN_Pin */
  GPIO_InitStruct.Pin = PWR_BTN_Pin;
  GPIO_InitStruct.Mode = GPIO_MODE_INPUT;
  GPIO_InitStruct.Pull = GPIO_NOPULL;
  HAL_GPIO_Init(PWR_BTN_GPIO_Port, &GPIO_InitStruct);

  /*Configure GPIO pin : TPS_ENA_Pin */
  GPIO_InitStruct.Pin = TPS_ENA_Pin;
  GPIO_InitStruct.Mode = GPIO_MODE_OUTPUT_PP;
  GPIO_InitStruct.Pull = GPIO_NOPULL;
  GPIO_InitStruct.Speed = GPIO_SPEED_FREQ_LOW;
  HAL_GPIO_Init(TPS_ENA_GPIO_Port, &GPIO_InitStruct);

  /*Configure GPIO pin : LED_Pin */
  GPIO_InitStruct.Pin = LED_Pin;
  GPIO_InitStruct.Mode = GPIO_MODE_OUTPUT_PP;
  GPIO_InitStruct.Pull = GPIO_NOPULL;
  GPIO_InitStruct.Speed = GPIO_SPEED_FREQ_LOW;
  HAL_GPIO_Init(LED_GPIO_Port, &GPIO_InitStruct);

  /*Configure GPIO pin : BRAKE_LIGHT_Pin */
  GPIO_InitStruct.Pin = BRAKE_LIGHT_Pin;
  GPIO_InitStruct.Mode = GPIO_MODE_OUTPUT_OD;
  GPIO_InitStruct.Pull = GPIO_NOPULL;
  GPIO_InitStruct.Speed = GPIO_SPEED_FREQ_LOW;
  HAL_GPIO_Init(BRAKE_LIGHT_GPIO_Port, &GPIO_InitStruct);

  /*Configure peripheral I/O remapping */
  __HAL_AFIO_REMAP_PD01_ENABLE();

}

/* USER CODE BEGIN 4 */
/* USER CODE BEGIN Header_startMediumFrequencyTask */
/**
  * @brief  Function implementing the mediumFrequency thread.
  * @param  argument: Not used
  * @retval None
  */
/* USER CODE END Header_startMediumFrequencyTask */

/* USER CODE END 4 */

void HAL_TIM_PeriodElapsedCallback(TIM_HandleTypeDef *htim)
{
  if (htim->Instance == TIM4) {
    HAL_IncTick();
  }
}

void Error_Handler(void)
{
  __disable_irq();
  while (1)
  {
  }
}

/************************ (C) COPYRIGHT STMicroelectronics *****END OF FILE****/
